VERSION 5.7 ;
  NOWIREEXTENSIONATPIN ON ;
  DIVIDERCHAR "/" ;
  BUSBITCHARS "[]" ;
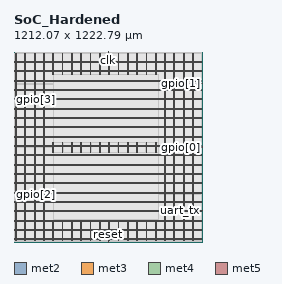
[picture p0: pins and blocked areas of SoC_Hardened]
MACRO SoC_Hardened
  CLASS BLOCK ;
  FOREIGN SoC_Hardened ;
  ORIGIN 0.000 0.000 ;
  SIZE 1212.070 BY 1222.790 ;
  PIN clk
    DIRECTION INPUT ;
    USE SIGNAL ;
    ANTENNAGATEAREA 1.704000 ;
    PORT
      LAYER met2 ;
        RECT 605.380 1218.790 605.800 1222.790 ;
    END
  END clk
  PIN gpio[0]
    DIRECTION OUTPUT ;
    USE SIGNAL ;
    ANTENNADIFFAREA 0.445500 ;
    PORT
      LAYER met3 ;
        RECT 1208.070 610.530 1212.070 611.430 ;
    END
  END gpio[0]
  PIN gpio[1]
    DIRECTION OUTPUT ;
    USE SIGNAL ;
    ANTENNADIFFAREA 2.673000 ;
    PORT
      LAYER met3 ;
        RECT 1208.070 1017.170 1212.070 1018.070 ;
    END
  END gpio[1]
  PIN gpio[2]
    DIRECTION OUTPUT ;
    USE SIGNAL ;
    ANTENNADIFFAREA 0.445500 ;
    PORT
      LAYER met3 ;
        RECT 0.000 304.530 4.000 305.430 ;
    END
  END gpio[2]
  PIN gpio[3]
    DIRECTION OUTPUT ;
    USE SIGNAL ;
    ANTENNADIFFAREA 1.782000 ;
    PORT
      LAYER met3 ;
        RECT 0.000 915.170 4.000 916.070 ;
    END
  END gpio[3]
  PIN reset
    DIRECTION INPUT ;
    USE SIGNAL ;
    ANTENNAGATEAREA 1.028400 ;
    ANTENNADIFFAREA 0.869400 ;
    PORT
      LAYER met2 ;
        RECT 605.380 0.000 605.800 4.000 ;
    END
  END reset
  PIN uart_tx
    DIRECTION OUTPUT ;
    USE SIGNAL ;
    ANTENNADIFFAREA 0.445500 ;
    PORT
      LAYER met3 ;
        RECT 1208.070 203.890 1212.070 204.790 ;
    END
  END uart_tx
  PIN vccd1
    DIRECTION INOUT ;
    USE POWER ;
    PORT
      LAYER met4 ;
        RECT 9.520 10.640 11.520 1210.640 ;
    END
    PORT
      LAYER met4 ;
        RECT 69.520 10.640 71.520 1210.640 ;
    END
    PORT
      LAYER met4 ;
        RECT 129.520 10.640 131.520 1210.640 ;
    END
    PORT
      LAYER met4 ;
        RECT 189.520 10.640 191.520 1210.640 ;
    END
    PORT
      LAYER met4 ;
        RECT 249.520 10.640 251.520 140.320 ;
    END
    PORT
      LAYER met4 ;
        RECT 249.520 576.220 251.520 640.320 ;
    END
    PORT
      LAYER met4 ;
        RECT 249.520 1076.220 251.520 1210.640 ;
    END
    PORT
      LAYER met4 ;
        RECT 309.520 10.640 311.520 140.320 ;
    END
    PORT
      LAYER met4 ;
        RECT 309.520 576.220 311.520 640.320 ;
    END
    PORT
      LAYER met4 ;
        RECT 309.520 1076.220 311.520 1210.640 ;
    END
    PORT
      LAYER met4 ;
        RECT 369.520 10.640 371.520 139.400 ;
    END
    PORT
      LAYER met4 ;
        RECT 369.520 576.220 371.520 639.440 ;
    END
    PORT
      LAYER met4 ;
        RECT 369.520 1076.220 371.520 1210.640 ;
    END
    PORT
      LAYER met4 ;
        RECT 429.520 10.640 431.520 139.400 ;
    END
    PORT
      LAYER met4 ;
        RECT 429.520 577.140 431.520 639.440 ;
    END
    PORT
      LAYER met4 ;
        RECT 429.520 1077.140 431.520 1210.640 ;
    END
    PORT
      LAYER met4 ;
        RECT 489.520 10.640 491.520 139.400 ;
    END
    PORT
      LAYER met4 ;
        RECT 489.520 576.220 491.520 639.440 ;
    END
    PORT
      LAYER met4 ;
        RECT 489.520 1076.220 491.520 1210.640 ;
    END
    PORT
      LAYER met4 ;
        RECT 549.520 10.640 551.520 140.320 ;
    END
    PORT
      LAYER met4 ;
        RECT 549.520 576.220 551.520 640.320 ;
    END
    PORT
      LAYER met4 ;
        RECT 549.520 1076.220 551.520 1210.640 ;
    END
    PORT
      LAYER met4 ;
        RECT 609.520 10.640 611.520 140.320 ;
    END
    PORT
      LAYER met4 ;
        RECT 609.520 576.220 611.520 640.320 ;
    END
    PORT
      LAYER met4 ;
        RECT 609.520 1076.220 611.520 1210.640 ;
    END
    PORT
      LAYER met4 ;
        RECT 669.520 10.640 671.520 140.320 ;
    END
    PORT
      LAYER met4 ;
        RECT 669.520 576.220 671.520 640.320 ;
    END
    PORT
      LAYER met4 ;
        RECT 669.520 1076.220 671.520 1210.640 ;
    END
    PORT
      LAYER met4 ;
        RECT 729.520 10.640 731.520 139.400 ;
    END
    PORT
      LAYER met4 ;
        RECT 729.520 577.140 731.520 639.440 ;
    END
    PORT
      LAYER met4 ;
        RECT 729.520 1077.140 731.520 1210.640 ;
    END
    PORT
      LAYER met4 ;
        RECT 789.520 10.640 791.520 140.320 ;
    END
    PORT
      LAYER met4 ;
        RECT 789.520 576.220 791.520 640.320 ;
    END
    PORT
      LAYER met4 ;
        RECT 789.520 1076.220 791.520 1210.640 ;
    END
    PORT
      LAYER met4 ;
        RECT 849.520 10.640 851.520 140.320 ;
    END
    PORT
      LAYER met4 ;
        RECT 849.520 576.220 851.520 640.320 ;
    END
    PORT
      LAYER met4 ;
        RECT 849.520 1076.220 851.520 1210.640 ;
    END
    PORT
      LAYER met4 ;
        RECT 909.520 10.640 911.520 140.320 ;
    END
    PORT
      LAYER met4 ;
        RECT 909.520 576.220 911.520 640.320 ;
    END
    PORT
      LAYER met4 ;
        RECT 909.520 1076.220 911.520 1210.640 ;
    END
    PORT
      LAYER met4 ;
        RECT 969.520 10.640 971.520 1210.640 ;
    END
    PORT
      LAYER met4 ;
        RECT 1029.520 10.640 1031.520 1210.640 ;
    END
    PORT
      LAYER met4 ;
        RECT 1089.520 10.640 1091.520 1210.640 ;
    END
    PORT
      LAYER met4 ;
        RECT 1149.520 10.640 1151.520 1210.640 ;
    END
    PORT
      LAYER met5 ;
        RECT 5.520 14.880 1206.120 16.880 ;
    END
    PORT
      LAYER met5 ;
        RECT 5.520 74.880 1206.120 76.880 ;
    END
    PORT
      LAYER met5 ;
        RECT 5.520 134.880 1206.120 136.880 ;
    END
    PORT
      LAYER met5 ;
        RECT 5.520 194.880 1206.120 196.880 ;
    END
    PORT
      LAYER met5 ;
        RECT 5.520 254.880 1206.120 256.880 ;
    END
    PORT
      LAYER met5 ;
        RECT 5.520 314.880 1206.120 316.880 ;
    END
    PORT
      LAYER met5 ;
        RECT 5.520 374.880 1206.120 376.880 ;
    END
    PORT
      LAYER met5 ;
        RECT 5.520 434.880 1206.120 436.880 ;
    END
    PORT
      LAYER met5 ;
        RECT 5.520 494.880 1206.120 496.880 ;
    END
    PORT
      LAYER met5 ;
        RECT 5.520 554.880 1206.120 556.880 ;
    END
    PORT
      LAYER met5 ;
        RECT 5.520 614.880 1206.120 616.880 ;
    END
    PORT
      LAYER met5 ;
        RECT 5.520 674.880 1206.120 676.880 ;
    END
    PORT
      LAYER met5 ;
        RECT 5.520 734.880 1206.120 736.880 ;
    END
    PORT
      LAYER met5 ;
        RECT 5.520 794.880 1206.120 796.880 ;
    END
    PORT
      LAYER met5 ;
        RECT 5.520 854.880 1206.120 856.880 ;
    END
    PORT
      LAYER met5 ;
        RECT 5.520 914.880 1206.120 916.880 ;
    END
    PORT
      LAYER met5 ;
        RECT 5.520 974.880 1206.120 976.880 ;
    END
    PORT
      LAYER met5 ;
        RECT 5.520 1034.880 1206.120 1036.880 ;
    END
    PORT
      LAYER met5 ;
        RECT 5.520 1094.880 1206.120 1096.880 ;
    END
    PORT
      LAYER met5 ;
        RECT 5.520 1154.880 1206.120 1156.880 ;
    END
  END vccd1
  PIN vssd1
    DIRECTION INOUT ;
    USE GROUND ;
    PORT
      LAYER met4 ;
        RECT 13.220 10.640 15.220 1210.640 ;
    END
    PORT
      LAYER met4 ;
        RECT 73.220 10.640 75.220 1210.640 ;
    END
    PORT
      LAYER met4 ;
        RECT 133.220 10.640 135.220 1210.640 ;
    END
    PORT
      LAYER met4 ;
        RECT 193.220 10.640 195.220 1210.640 ;
    END
    PORT
      LAYER met4 ;
        RECT 253.220 10.640 255.220 140.580 ;
    END
    PORT
      LAYER met4 ;
        RECT 253.220 576.220 255.220 640.320 ;
    END
    PORT
      LAYER met4 ;
        RECT 253.220 1076.220 255.220 1210.640 ;
    END
    PORT
      LAYER met4 ;
        RECT 313.220 10.640 315.220 140.580 ;
    END
    PORT
      LAYER met4 ;
        RECT 313.220 576.220 315.220 640.320 ;
    END
    PORT
      LAYER met4 ;
        RECT 313.220 1076.220 315.220 1210.640 ;
    END
    PORT
      LAYER met4 ;
        RECT 373.220 10.640 375.220 140.580 ;
    END
    PORT
      LAYER met4 ;
        RECT 373.220 576.220 375.220 640.320 ;
    END
    PORT
      LAYER met4 ;
        RECT 373.220 1076.220 375.220 1210.640 ;
    END
    PORT
      LAYER met4 ;
        RECT 433.220 10.640 435.220 139.400 ;
    END
    PORT
      LAYER met4 ;
        RECT 433.220 576.220 435.220 639.400 ;
    END
    PORT
      LAYER met4 ;
        RECT 433.220 1076.220 435.220 1210.640 ;
    END
    PORT
      LAYER met4 ;
        RECT 493.220 10.640 495.220 139.400 ;
    END
    PORT
      LAYER met4 ;
        RECT 493.220 577.140 495.220 639.400 ;
    END
    PORT
      LAYER met4 ;
        RECT 493.220 1076.880 495.220 1210.640 ;
    END
    PORT
      LAYER met4 ;
        RECT 553.220 10.640 555.220 139.400 ;
    END
    PORT
      LAYER met4 ;
        RECT 553.220 577.140 555.220 639.400 ;
    END
    PORT
      LAYER met4 ;
        RECT 553.220 1076.880 555.220 1210.640 ;
    END
    PORT
      LAYER met4 ;
        RECT 613.220 10.640 615.220 140.580 ;
    END
    PORT
      LAYER met4 ;
        RECT 613.220 576.220 615.220 640.320 ;
    END
    PORT
      LAYER met4 ;
        RECT 613.220 1076.220 615.220 1210.640 ;
    END
    PORT
      LAYER met4 ;
        RECT 673.220 10.640 675.220 140.580 ;
    END
    PORT
      LAYER met4 ;
        RECT 673.220 576.220 675.220 640.320 ;
    END
    PORT
      LAYER met4 ;
        RECT 673.220 1076.220 675.220 1210.640 ;
    END
    PORT
      LAYER met4 ;
        RECT 733.220 10.640 735.220 140.580 ;
    END
    PORT
      LAYER met4 ;
        RECT 733.220 576.220 735.220 640.320 ;
    END
    PORT
      LAYER met4 ;
        RECT 733.220 1076.220 735.220 1210.640 ;
    END
    PORT
      LAYER met4 ;
        RECT 793.220 10.640 795.220 140.580 ;
    END
    PORT
      LAYER met4 ;
        RECT 793.220 576.220 795.220 640.320 ;
    END
    PORT
      LAYER met4 ;
        RECT 793.220 1076.220 795.220 1210.640 ;
    END
    PORT
      LAYER met4 ;
        RECT 853.220 10.640 855.220 140.580 ;
    END
    PORT
      LAYER met4 ;
        RECT 853.220 576.220 855.220 640.320 ;
    END
    PORT
      LAYER met4 ;
        RECT 853.220 1076.220 855.220 1210.640 ;
    END
    PORT
      LAYER met4 ;
        RECT 913.220 10.640 915.220 140.580 ;
    END
    PORT
      LAYER met4 ;
        RECT 913.220 576.220 915.220 640.320 ;
    END
    PORT
      LAYER met4 ;
        RECT 913.220 1076.220 915.220 1210.640 ;
    END
    PORT
      LAYER met4 ;
        RECT 973.220 10.640 975.220 1210.640 ;
    END
    PORT
      LAYER met4 ;
        RECT 1033.220 10.640 1035.220 1210.640 ;
    END
    PORT
      LAYER met4 ;
        RECT 1093.220 10.640 1095.220 1210.640 ;
    END
    PORT
      LAYER met4 ;
        RECT 1153.220 10.640 1155.220 1210.640 ;
    END
    PORT
      LAYER met5 ;
        RECT 5.520 18.580 1206.120 20.580 ;
    END
    PORT
      LAYER met5 ;
        RECT 5.520 78.580 1206.120 80.580 ;
    END
    PORT
      LAYER met5 ;
        RECT 5.520 138.580 1206.120 140.580 ;
    END
    PORT
      LAYER met5 ;
        RECT 5.520 198.580 1206.120 200.580 ;
    END
    PORT
      LAYER met5 ;
        RECT 5.520 258.580 1206.120 260.580 ;
    END
    PORT
      LAYER met5 ;
        RECT 5.520 318.580 1206.120 320.580 ;
    END
    PORT
      LAYER met5 ;
        RECT 5.520 378.580 1206.120 380.580 ;
    END
    PORT
      LAYER met5 ;
        RECT 5.520 438.580 1206.120 440.580 ;
    END
    PORT
      LAYER met5 ;
        RECT 5.520 498.580 1206.120 500.580 ;
    END
    PORT
      LAYER met5 ;
        RECT 5.520 558.580 1206.120 560.580 ;
    END
    PORT
      LAYER met5 ;
        RECT 5.520 618.580 1206.120 620.580 ;
    END
    PORT
      LAYER met5 ;
        RECT 5.520 678.580 1206.120 680.580 ;
    END
    PORT
      LAYER met5 ;
        RECT 5.520 738.580 1206.120 740.580 ;
    END
    PORT
      LAYER met5 ;
        RECT 5.520 798.580 1206.120 800.580 ;
    END
    PORT
      LAYER met5 ;
        RECT 5.520 858.580 1206.120 860.580 ;
    END
    PORT
      LAYER met5 ;
        RECT 5.520 918.580 1206.120 920.580 ;
    END
    PORT
      LAYER met5 ;
        RECT 5.520 978.580 1206.120 980.580 ;
    END
    PORT
      LAYER met5 ;
        RECT 5.520 1038.580 1206.120 1040.580 ;
    END
    PORT
      LAYER met5 ;
        RECT 5.520 1098.580 1206.120 1100.580 ;
    END
    PORT
      LAYER met5 ;
        RECT 5.520 1158.580 1206.120 1160.580 ;
    END
  END vssd1
  OBS
      LAYER nwell ;
        RECT 5.330 10.795 1206.310 1210.590 ;
      LAYER li1 ;
        RECT 5.520 10.795 1206.120 1210.485 ;
      LAYER met1 ;
        RECT 5.520 0.380 1206.120 1210.640 ;
      LAYER met2 ;
        RECT 6.530 1218.510 605.100 1218.790 ;
        RECT 606.080 1218.510 1203.730 1218.790 ;
        RECT 6.530 4.280 1203.730 1218.510 ;
        RECT 6.530 0.350 605.100 4.280 ;
        RECT 606.080 0.350 1203.730 4.280 ;
      LAYER met3 ;
        RECT 4.000 1018.470 1208.070 1210.565 ;
        RECT 4.000 1016.770 1207.670 1018.470 ;
        RECT 4.000 916.470 1208.070 1016.770 ;
        RECT 4.400 914.770 1208.070 916.470 ;
        RECT 4.000 611.830 1208.070 914.770 ;
        RECT 4.000 610.130 1207.670 611.830 ;
        RECT 4.000 305.830 1208.070 610.130 ;
        RECT 4.400 304.130 1208.070 305.830 ;
        RECT 4.000 205.190 1208.070 304.130 ;
        RECT 4.000 203.490 1207.670 205.190 ;
        RECT 4.000 10.715 1208.070 203.490 ;
      LAYER met4 ;
        RECT 251.920 1075.820 252.820 1076.945 ;
        RECT 255.620 1075.820 309.120 1076.945 ;
        RECT 311.920 1075.820 312.820 1076.945 ;
        RECT 315.620 1075.820 369.120 1076.945 ;
        RECT 371.920 1075.820 372.820 1076.945 ;
        RECT 375.620 1076.740 429.120 1076.945 ;
        RECT 431.920 1076.740 432.820 1076.945 ;
        RECT 375.620 1075.820 432.820 1076.740 ;
        RECT 435.620 1075.820 489.120 1076.945 ;
        RECT 491.920 1076.480 492.820 1076.945 ;
        RECT 495.620 1076.480 549.120 1076.945 ;
        RECT 491.920 1075.820 549.120 1076.480 ;
        RECT 551.920 1076.480 552.820 1076.945 ;
        RECT 555.620 1076.480 609.120 1076.945 ;
        RECT 551.920 1075.820 609.120 1076.480 ;
        RECT 611.920 1075.820 612.820 1076.945 ;
        RECT 615.620 1075.820 669.120 1076.945 ;
        RECT 671.920 1075.820 672.820 1076.945 ;
        RECT 675.620 1076.740 729.120 1076.945 ;
        RECT 731.920 1076.740 732.820 1076.945 ;
        RECT 675.620 1075.820 732.820 1076.740 ;
        RECT 735.620 1075.820 789.120 1076.945 ;
        RECT 791.920 1075.820 792.820 1076.945 ;
        RECT 795.620 1075.820 849.120 1076.945 ;
        RECT 851.920 1075.820 852.820 1076.945 ;
        RECT 855.620 1075.820 909.120 1076.945 ;
        RECT 911.920 1075.820 912.820 1076.945 ;
        RECT 915.620 1075.820 931.740 1076.945 ;
        RECT 251.360 640.720 931.740 1075.820 ;
        RECT 251.920 575.820 252.820 640.720 ;
        RECT 255.620 575.820 309.120 640.720 ;
        RECT 311.920 575.820 312.820 640.720 ;
        RECT 315.620 639.840 372.820 640.720 ;
        RECT 315.620 575.820 369.120 639.840 ;
        RECT 371.920 575.820 372.820 639.840 ;
        RECT 375.620 639.840 549.120 640.720 ;
        RECT 375.620 576.740 429.120 639.840 ;
        RECT 431.920 639.800 489.120 639.840 ;
        RECT 431.920 576.740 432.820 639.800 ;
        RECT 375.620 575.820 432.820 576.740 ;
        RECT 435.620 575.820 489.120 639.800 ;
        RECT 491.920 639.800 549.120 639.840 ;
        RECT 491.920 576.740 492.820 639.800 ;
        RECT 495.620 576.740 549.120 639.800 ;
        RECT 491.920 575.820 549.120 576.740 ;
        RECT 551.920 639.800 609.120 640.720 ;
        RECT 551.920 576.740 552.820 639.800 ;
        RECT 555.620 576.740 609.120 639.800 ;
        RECT 551.920 575.820 609.120 576.740 ;
        RECT 611.920 575.820 612.820 640.720 ;
        RECT 615.620 575.820 669.120 640.720 ;
        RECT 671.920 575.820 672.820 640.720 ;
        RECT 675.620 639.840 732.820 640.720 ;
        RECT 675.620 576.740 729.120 639.840 ;
        RECT 731.920 576.740 732.820 639.840 ;
        RECT 675.620 575.820 732.820 576.740 ;
        RECT 735.620 575.820 789.120 640.720 ;
        RECT 791.920 575.820 792.820 640.720 ;
        RECT 795.620 575.820 849.120 640.720 ;
        RECT 851.920 575.820 852.820 640.720 ;
        RECT 855.620 575.820 909.120 640.720 ;
        RECT 911.920 575.820 912.820 640.720 ;
        RECT 915.620 575.820 931.740 640.720 ;
        RECT 251.360 143.655 931.740 575.820 ;
  END
END SoC_Hardened
END LIBRARY

